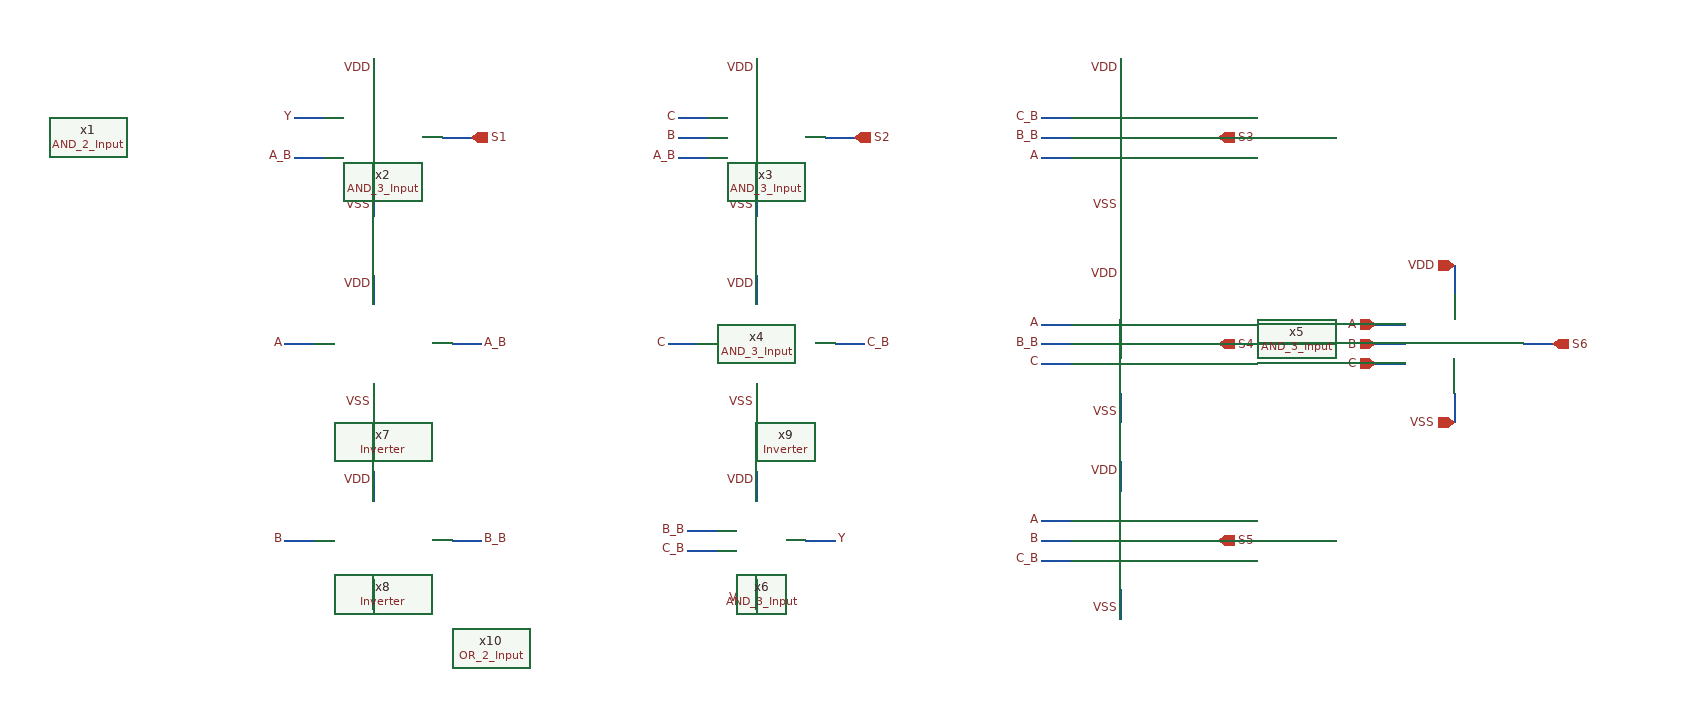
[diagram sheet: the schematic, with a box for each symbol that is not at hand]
v {xschem version=3.1.0 file_version=1.2
}
G {}
K {}
V {}
S {}
E {}
N 1160 -360 1190 -360 {
lab=A}
N 1160 -340 1190 -340 {
lab=B}
N 1160 -320 1190 -320 {
lab=C}
N 1310 -340 1340 -340 {
lab=S6}
N 1240 -420 1240 -390 {
lab=VDD}
N 1240 -290 1240 -260 {
lab=VSS}
N 820 -360 850 -360 {
lab=A}
N 820 -340 850 -340 {
lab=B_B}
N 820 -320 850 -320 {
lab=C}
N 970 -340 1000 -340 {
lab=S4}
N 900 -420 900 -390 {
lab=VDD}
N 900 -290 900 -260 {
lab=VSS}
N 820 -160 850 -160 {
lab=A}
N 820 -140 850 -140 {
lab=B}
N 820 -120 850 -120 {
lab=C_B}
N 970 -140 1000 -140 {
lab=S5}
N 900 -220 900 -190 {
lab=VDD}
N 900 -90 900 -60 {
lab=VSS}
N 820 -570 850 -570 {
lab=C_B}
N 820 -550 850 -550 {
lab=B_B}
N 820 -530 850 -530 {
lab=#net1}
N 970 -550 1000 -550 {
lab=S3}
N 900 -630 900 -600 {
lab=VDD}
N 900 -500 900 -470 {
lab=VSS}
N 450 -570 480 -570 {
lab=C}
N 450 -550 480 -550 {
lab=B}
N 450 -530 480 -530 {
lab=A_B}
N 600 -550 630 -550 {
lab=S2}
N 530 -630 530 -600 {
lab=VDD}
N 530 -500 530 -470 {
lab=VSS}
N 140 -630 140 -600 {
lab=VDD}
N 140 -500 140 -470 {
lab=VSS}
N 210 -550 240 -550 {
lab=S1}
N 60 -570 90 -570 {
lab=Y}
N 60 -530 90 -530 {
lab=A_B}
N 140 -210 140 -180 {
lab=VDD}
N 140 -100 140 -70 {
lab=VSS}
N 220 -140 250 -140 {
lab=B_B}
N 50 -140 80 -140 {
lab=B}
N 530 -410 530 -380 {
lab=VDD}
N 530 -300 530 -270 {
lab=VSS}
N 610 -340 640 -340 {
lab=C_B}
N 440 -340 470 -340 {
lab=C}
N 140 -410 140 -380 {
lab=VDD}
N 140 -300 140 -270 {
lab=VSS}
N 220 -340 250 -340 {
lab=A_B}
N 50 -340 80 -340 {
lab=A}
N 530 -210 530 -180 {
lab=VDD}
N 530 -100 530 -70 {
lab=VSS}
N 580 -140 610 -140 {
lab=Y}
N 460 -150 490 -150 {
lab=B_B}
N 460 -130 490 -130 {
lab=C_B}
C {devices/lab_pin.sym} 900 -410 0 0 {name=p7 sig_type=std_logic lab=VDD}
C {devices/lab_pin.sym} 900 -270 0 0 {name=p8 sig_type=std_logic lab=VSS}
C {devices/lab_pin.sym} 820 -360 0 0 {name=p9 sig_type=std_logic lab=A}
C {devices/lab_pin.sym} 820 -340 0 0 {name=p10 sig_type=std_logic lab=B_B}
C {devices/lab_pin.sym} 820 -320 0 0 {name=p11 sig_type=std_logic lab=C}
C {devices/lab_pin.sym} 900 -210 0 0 {name=p13 sig_type=std_logic lab=VDD}
C {devices/lab_pin.sym} 900 -70 0 0 {name=p14 sig_type=std_logic lab=VSS}
C {devices/lab_pin.sym} 820 -160 0 0 {name=p15 sig_type=std_logic lab=A}
C {devices/lab_pin.sym} 820 -140 0 0 {name=p16 sig_type=std_logic lab=B}
C {devices/lab_pin.sym} 820 -120 0 0 {name=p17 sig_type=std_logic lab=C_B}
C {devices/lab_pin.sym} 900 -620 0 0 {name=p19 sig_type=std_logic lab=VDD}
C {devices/lab_pin.sym} 900 -480 0 0 {name=p20 sig_type=std_logic lab=VSS}
C {devices/lab_pin.sym} 820 -530 0 0 {name=p21 sig_type=std_logic lab=A}
C {devices/lab_pin.sym} 820 -550 0 0 {name=p22 sig_type=std_logic lab=B_B}
C {devices/lab_pin.sym} 820 -570 0 0 {name=p23 sig_type=std_logic lab=C_B}
C {devices/lab_pin.sym} 530 -620 0 0 {name=p25 sig_type=std_logic lab=VDD}
C {devices/lab_pin.sym} 530 -480 0 0 {name=p26 sig_type=std_logic lab=VSS}
C {devices/lab_pin.sym} 450 -530 0 0 {name=p27 sig_type=std_logic lab=A_B}
C {devices/lab_pin.sym} 450 -550 0 0 {name=p28 sig_type=std_logic lab=B}
C {devices/lab_pin.sym} 450 -570 0 0 {name=p29 sig_type=std_logic lab=C}
C {devices/lab_pin.sym} 140 -620 0 0 {name=p31 sig_type=std_logic lab=VDD}
C {devices/lab_pin.sym} 140 -480 0 0 {name=p32 sig_type=std_logic lab=VSS}
C {devices/lab_pin.sym} 60 -530 0 0 {name=p34 sig_type=std_logic lab=A_B}
C {devices/lab_pin.sym} 60 -570 0 0 {name=p35 sig_type=std_logic lab=Y}
C {devices/lab_pin.sym} 140 -200 0 0 {name=p36 sig_type=std_logic lab=VDD}
C {devices/lab_pin.sym} 140 -80 0 0 {name=p37 sig_type=std_logic lab=VSS}
C {devices/lab_pin.sym} 250 -140 0 1 {name=p38 sig_type=std_logic lab=B_B}
C {devices/lab_pin.sym} 50 -140 0 0 {name=p39 sig_type=std_logic lab=B}
C {devices/lab_pin.sym} 530 -400 0 0 {name=p40 sig_type=std_logic lab=VDD}
C {devices/lab_pin.sym} 530 -280 0 0 {name=p41 sig_type=std_logic lab=VSS}
C {devices/lab_pin.sym} 640 -340 0 1 {name=p42 sig_type=std_logic lab=C_B}
C {devices/lab_pin.sym} 440 -340 0 0 {name=p43 sig_type=std_logic lab=C}
C {devices/lab_pin.sym} 140 -400 0 0 {name=p44 sig_type=std_logic lab=VDD}
C {devices/lab_pin.sym} 140 -280 0 0 {name=p45 sig_type=std_logic lab=VSS}
C {devices/lab_pin.sym} 250 -340 0 1 {name=p46 sig_type=std_logic lab=A_B}
C {devices/lab_pin.sym} 50 -340 0 0 {name=p47 sig_type=std_logic lab=A}
C {devices/lab_pin.sym} 530 -200 0 0 {name=p48 sig_type=std_logic lab=VDD}
C {devices/lab_pin.sym} 530 -80 0 0 {name=p49 sig_type=std_logic lab=VSS}
C {devices/lab_pin.sym} 610 -140 0 1 {name=p50 sig_type=std_logic lab=Y}
C {devices/lab_pin.sym} 460 -150 0 0 {name=p51 sig_type=std_logic lab=B_B}
C {devices/lab_pin.sym} 460 -130 0 0 {name=p52 sig_type=std_logic lab=C_B}
C {devices/opin.sym} 240 -550 0 0 {name=p33 lab=S1}
C {devices/opin.sym} 630 -550 0 0 {name=p30 lab=S2}
C {devices/opin.sym} 1000 -550 0 0 {name=p24 lab=S3}
C {devices/opin.sym} 1000 -340 0 0 {name=p12 lab=S4}
C {devices/opin.sym} 1000 -140 0 0 {name=p18 lab=S5}
C {devices/opin.sym} 1340 -340 0 0 {name=p6 lab=S6}
C {devices/ipin.sym} 1160 -360 0 0 {name=p3 lab=A}
C {devices/ipin.sym} 1160 -340 0 0 {name=p4 lab=B}
C {devices/ipin.sym} 1160 -320 0 0 {name=p5 lab=C}
C {devices/iopin.sym} 1240 -420 0 0 {name=p1 lab=VDD}
C {devices/iopin.sym} 1240 -260 0 0 {name=p53 lab=VSS}
C {/home/shahid/GF180Projects/Tapeout/Xschem/Logic_Gates/AND_2_Input.sym} -150 -550 0 0 {name=x1}
C {/home/shahid/GF180Projects/Tapeout/Xschem/Logic_Gates/AND_3_Input.sym} 110 -480 0 0 {name=x2}
C {/home/shahid/GF180Projects/Tapeout/Xschem/Logic_Gates/AND_3_Input.sym} 480 -480 0 0 {name=x3}
C {/home/shahid/GF180Projects/Tapeout/Xschem/Logic_Gates/AND_3_Input.sym} 480 -270 0 0 {name=x4}
C {/home/shahid/GF180Projects/Tapeout/Xschem/Logic_Gates/AND_3_Input.sym} 820 -270 0 0 {name=x5}
C {/home/shahid/GF180Projects/Tapeout/Xschem/Logic_Gates/AND_3_Input.sym} 480 -70 0 0 {name=x6}
C {/home/shahid/GF180Projects/Tapeout/Xschem/Logic_Gates/Inverter.sym} 170 -270 0 0 {name=x7}
C {/home/shahid/GF180Projects/Tapeout/Xschem/Logic_Gates/Inverter.sym} 170 -70 0 0 {name=x8}
C {/home/shahid/GF180Projects/Tapeout/Xschem/Logic_Gates/Inverter.sym} 560 -270 0 0 {name=x9}
C {/home/shahid/GF180Projects/Tapeout/Xschem/Logic_Gates/OR_2_Input.sym} 260 -30 0 0 {name=x10}
